VERSION 5.7 ;
  NOWIREEXTENSIONATPIN ON ;
  DIVIDERCHAR "/" ;
  BUSBITCHARS "[]" ;
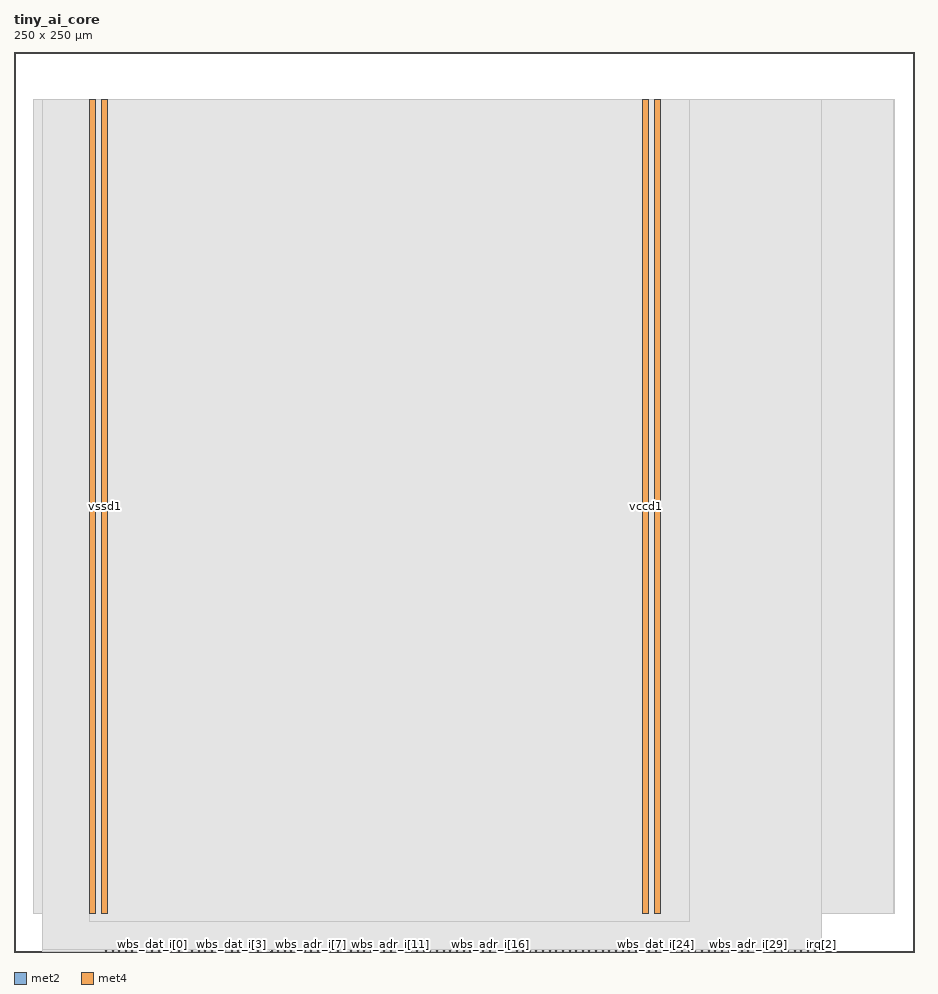
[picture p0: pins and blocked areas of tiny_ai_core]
MACRO tiny_ai_core
  CLASS BLOCK ;
  FOREIGN tiny_ai_core ;
  ORIGIN 0.000 0.000 ;
  SIZE 250.000 BY 250.000 ;
  PIN irq[0]
    DIRECTION OUTPUT ;
    USE SIGNAL ;
    ANTENNADIFFAREA 2.673000 ;
    PORT
      LAYER met2 ;
        RECT 220.430 0.000 220.710 0.280 ;
    END
  END irq[0]
  PIN irq[1]
    DIRECTION OUTPUT ;
    USE SIGNAL ;
    PORT
      LAYER met2 ;
        RECT 222.270 0.000 222.550 0.280 ;
    END
  END irq[1]
  PIN irq[2]
    DIRECTION OUTPUT ;
    USE SIGNAL ;
    PORT
      LAYER met2 ;
        RECT 224.110 0.000 224.390 0.280 ;
    END
  END irq[2]
  PIN vccd1
    DIRECTION INOUT ;
    USE POWER ;
    PORT
      LAYER met4 ;
        RECT 21.040 10.640 22.640 236.880 ;
    END
    PORT
      LAYER met4 ;
        RECT 174.640 10.640 176.240 236.880 ;
    END
  END vccd1
  PIN vssd1
    DIRECTION INOUT ;
    USE GROUND ;
    PORT
      LAYER met4 ;
        RECT 24.340 10.640 25.940 236.880 ;
    END
    PORT
      LAYER met4 ;
        RECT 177.940 10.640 179.540 236.880 ;
    END
  END vssd1
  PIN wb_clk_i
    DIRECTION INPUT ;
    USE SIGNAL ;
    ANTENNAGATEAREA 1.286700 ;
    ANTENNADIFFAREA 0.434700 ;
    PORT
      LAYER met2 ;
        RECT 25.390 0.000 25.670 0.280 ;
    END
  END wb_clk_i
  PIN wb_rst_i
    DIRECTION INPUT ;
    USE SIGNAL ;
    ANTENNAGATEAREA 0.647700 ;
    ANTENNADIFFAREA 0.434700 ;
    PORT
      LAYER met2 ;
        RECT 27.230 0.000 27.510 0.280 ;
    END
  END wb_rst_i
  PIN wbs_ack_o
    DIRECTION OUTPUT ;
    USE SIGNAL ;
    ANTENNADIFFAREA 2.673000 ;
    PORT
      LAYER met2 ;
        RECT 29.070 0.000 29.350 0.280 ;
    END
  END wbs_ack_o
  PIN wbs_adr_i[0]
    DIRECTION INPUT ;
    USE SIGNAL ;
    PORT
      LAYER met2 ;
        RECT 36.430 0.000 36.710 0.280 ;
    END
  END wbs_adr_i[0]
  PIN wbs_adr_i[10]
    DIRECTION INPUT ;
    USE SIGNAL ;
    ANTENNAGATEAREA 0.560700 ;
    ANTENNADIFFAREA 0.434700 ;
    PORT
      LAYER met2 ;
        RECT 98.990 0.000 99.270 0.280 ;
    END
  END wbs_adr_i[10]
  PIN wbs_adr_i[11]
    DIRECTION INPUT ;
    USE SIGNAL ;
    ANTENNAGATEAREA 0.647700 ;
    ANTENNADIFFAREA 0.434700 ;
    PORT
      LAYER met2 ;
        RECT 104.510 0.000 104.790 0.280 ;
    END
  END wbs_adr_i[11]
  PIN wbs_adr_i[12]
    DIRECTION INPUT ;
    USE SIGNAL ;
    ANTENNAGATEAREA 0.647700 ;
    ANTENNADIFFAREA 0.434700 ;
    PORT
      LAYER met2 ;
        RECT 110.030 0.000 110.310 0.280 ;
    END
  END wbs_adr_i[12]
  PIN wbs_adr_i[13]
    DIRECTION INPUT ;
    USE SIGNAL ;
    ANTENNAGATEAREA 0.647700 ;
    ANTENNADIFFAREA 0.434700 ;
    PORT
      LAYER met2 ;
        RECT 115.550 0.000 115.830 0.280 ;
    END
  END wbs_adr_i[13]
  PIN wbs_adr_i[14]
    DIRECTION INPUT ;
    USE SIGNAL ;
    ANTENNAGATEAREA 0.647700 ;
    ANTENNADIFFAREA 0.434700 ;
    PORT
      LAYER met2 ;
        RECT 121.070 0.000 121.350 0.280 ;
    END
  END wbs_adr_i[14]
  PIN wbs_adr_i[15]
    DIRECTION INPUT ;
    USE SIGNAL ;
    ANTENNAGATEAREA 0.647700 ;
    ANTENNADIFFAREA 0.434700 ;
    PORT
      LAYER met2 ;
        RECT 126.590 0.000 126.870 0.280 ;
    END
  END wbs_adr_i[15]
  PIN wbs_adr_i[16]
    DIRECTION INPUT ;
    USE SIGNAL ;
    ANTENNAGATEAREA 0.647700 ;
    ANTENNADIFFAREA 0.434700 ;
    PORT
      LAYER met2 ;
        RECT 132.110 0.000 132.390 0.280 ;
    END
  END wbs_adr_i[16]
  PIN wbs_adr_i[17]
    DIRECTION INPUT ;
    USE SIGNAL ;
    ANTENNAGATEAREA 0.647700 ;
    ANTENNADIFFAREA 0.434700 ;
    PORT
      LAYER met2 ;
        RECT 137.630 0.000 137.910 0.280 ;
    END
  END wbs_adr_i[17]
  PIN wbs_adr_i[18]
    DIRECTION INPUT ;
    USE SIGNAL ;
    ANTENNAGATEAREA 0.647700 ;
    ANTENNADIFFAREA 0.434700 ;
    PORT
      LAYER met2 ;
        RECT 143.150 0.000 143.430 0.280 ;
    END
  END wbs_adr_i[18]
  PIN wbs_adr_i[19]
    DIRECTION INPUT ;
    USE SIGNAL ;
    ANTENNAGATEAREA 0.647700 ;
    ANTENNADIFFAREA 0.434700 ;
    PORT
      LAYER met2 ;
        RECT 148.670 0.000 148.950 0.280 ;
    END
  END wbs_adr_i[19]
  PIN wbs_adr_i[1]
    DIRECTION INPUT ;
    USE SIGNAL ;
    PORT
      LAYER met2 ;
        RECT 43.790 0.000 44.070 0.280 ;
    END
  END wbs_adr_i[1]
  PIN wbs_adr_i[20]
    DIRECTION INPUT ;
    USE SIGNAL ;
    ANTENNAGATEAREA 0.647700 ;
    ANTENNADIFFAREA 0.434700 ;
    PORT
      LAYER met2 ;
        RECT 154.190 0.000 154.470 0.280 ;
    END
  END wbs_adr_i[20]
  PIN wbs_adr_i[21]
    DIRECTION INPUT ;
    USE SIGNAL ;
    ANTENNAGATEAREA 0.647700 ;
    ANTENNADIFFAREA 0.434700 ;
    PORT
      LAYER met2 ;
        RECT 159.710 0.000 159.990 0.280 ;
    END
  END wbs_adr_i[21]
  PIN wbs_adr_i[22]
    DIRECTION INPUT ;
    USE SIGNAL ;
    ANTENNAGATEAREA 0.647700 ;
    ANTENNADIFFAREA 0.434700 ;
    PORT
      LAYER met2 ;
        RECT 165.230 0.000 165.510 0.280 ;
    END
  END wbs_adr_i[22]
  PIN wbs_adr_i[23]
    DIRECTION INPUT ;
    USE SIGNAL ;
    ANTENNAGATEAREA 0.647700 ;
    ANTENNADIFFAREA 0.434700 ;
    PORT
      LAYER met2 ;
        RECT 170.750 0.000 171.030 0.280 ;
    END
  END wbs_adr_i[23]
  PIN wbs_adr_i[24]
    DIRECTION INPUT ;
    USE SIGNAL ;
    ANTENNAGATEAREA 0.647700 ;
    ANTENNADIFFAREA 0.434700 ;
    PORT
      LAYER met2 ;
        RECT 176.270 0.000 176.550 0.280 ;
    END
  END wbs_adr_i[24]
  PIN wbs_adr_i[25]
    DIRECTION INPUT ;
    USE SIGNAL ;
    ANTENNAGATEAREA 0.647700 ;
    ANTENNADIFFAREA 0.434700 ;
    PORT
      LAYER met2 ;
        RECT 181.790 0.000 182.070 0.280 ;
    END
  END wbs_adr_i[25]
  PIN wbs_adr_i[26]
    DIRECTION INPUT ;
    USE SIGNAL ;
    ANTENNAGATEAREA 0.560700 ;
    ANTENNADIFFAREA 0.434700 ;
    PORT
      LAYER met2 ;
        RECT 187.310 0.000 187.590 0.280 ;
    END
  END wbs_adr_i[26]
  PIN wbs_adr_i[27]
    DIRECTION INPUT ;
    USE SIGNAL ;
    ANTENNAGATEAREA 0.647700 ;
    ANTENNADIFFAREA 0.434700 ;
    PORT
      LAYER met2 ;
        RECT 192.830 0.000 193.110 0.280 ;
    END
  END wbs_adr_i[27]
  PIN wbs_adr_i[28]
    DIRECTION INPUT ;
    USE SIGNAL ;
    ANTENNAGATEAREA 0.647700 ;
    ANTENNADIFFAREA 0.434700 ;
    PORT
      LAYER met2 ;
        RECT 198.350 0.000 198.630 0.280 ;
    END
  END wbs_adr_i[28]
  PIN wbs_adr_i[29]
    DIRECTION INPUT ;
    USE SIGNAL ;
    ANTENNAGATEAREA 0.647700 ;
    ANTENNADIFFAREA 0.434700 ;
    PORT
      LAYER met2 ;
        RECT 203.870 0.000 204.150 0.280 ;
    END
  END wbs_adr_i[29]
  PIN wbs_adr_i[2]
    DIRECTION INPUT ;
    USE SIGNAL ;
    ANTENNAGATEAREA 0.647700 ;
    ANTENNADIFFAREA 0.434700 ;
    PORT
      LAYER met2 ;
        RECT 51.150 0.000 51.430 0.280 ;
    END
  END wbs_adr_i[2]
  PIN wbs_adr_i[30]
    DIRECTION INPUT ;
    USE SIGNAL ;
    ANTENNAGATEAREA 0.647700 ;
    ANTENNADIFFAREA 0.434700 ;
    PORT
      LAYER met2 ;
        RECT 209.390 0.000 209.670 0.280 ;
    END
  END wbs_adr_i[30]
  PIN wbs_adr_i[31]
    DIRECTION INPUT ;
    USE SIGNAL ;
    ANTENNAGATEAREA 0.647700 ;
    ANTENNADIFFAREA 0.434700 ;
    PORT
      LAYER met2 ;
        RECT 214.910 0.000 215.190 0.280 ;
    END
  END wbs_adr_i[31]
  PIN wbs_adr_i[3]
    DIRECTION INPUT ;
    USE SIGNAL ;
    ANTENNAGATEAREA 0.560700 ;
    ANTENNADIFFAREA 0.434700 ;
    PORT
      LAYER met2 ;
        RECT 58.510 0.000 58.790 0.280 ;
    END
  END wbs_adr_i[3]
  PIN wbs_adr_i[4]
    DIRECTION INPUT ;
    USE SIGNAL ;
    ANTENNAGATEAREA 0.647700 ;
    ANTENNADIFFAREA 0.434700 ;
    PORT
      LAYER met2 ;
        RECT 65.870 0.000 66.150 0.280 ;
    END
  END wbs_adr_i[4]
  PIN wbs_adr_i[5]
    DIRECTION INPUT ;
    USE SIGNAL ;
    ANTENNAGATEAREA 0.647700 ;
    ANTENNADIFFAREA 0.434700 ;
    PORT
      LAYER met2 ;
        RECT 71.390 0.000 71.670 0.280 ;
    END
  END wbs_adr_i[5]
  PIN wbs_adr_i[6]
    DIRECTION INPUT ;
    USE SIGNAL ;
    ANTENNAGATEAREA 0.560700 ;
    ANTENNADIFFAREA 0.434700 ;
    PORT
      LAYER met2 ;
        RECT 76.910 0.000 77.190 0.280 ;
    END
  END wbs_adr_i[6]
  PIN wbs_adr_i[7]
    DIRECTION INPUT ;
    USE SIGNAL ;
    ANTENNAGATEAREA 0.647700 ;
    ANTENNADIFFAREA 0.434700 ;
    PORT
      LAYER met2 ;
        RECT 82.430 0.000 82.710 0.280 ;
    END
  END wbs_adr_i[7]
  PIN wbs_adr_i[8]
    DIRECTION INPUT ;
    USE SIGNAL ;
    ANTENNAGATEAREA 0.647700 ;
    ANTENNADIFFAREA 0.434700 ;
    PORT
      LAYER met2 ;
        RECT 87.950 0.000 88.230 0.280 ;
    END
  END wbs_adr_i[8]
  PIN wbs_adr_i[9]
    DIRECTION INPUT ;
    USE SIGNAL ;
    ANTENNAGATEAREA 0.647700 ;
    ANTENNADIFFAREA 0.434700 ;
    PORT
      LAYER met2 ;
        RECT 93.470 0.000 93.750 0.280 ;
    END
  END wbs_adr_i[9]
  PIN wbs_cyc_i
    DIRECTION INPUT ;
    USE SIGNAL ;
    ANTENNAGATEAREA 0.560700 ;
    ANTENNADIFFAREA 0.434700 ;
    PORT
      LAYER met2 ;
        RECT 30.910 0.000 31.190 0.280 ;
    END
  END wbs_cyc_i
  PIN wbs_dat_i[0]
    DIRECTION INPUT ;
    USE SIGNAL ;
    ANTENNAGATEAREA 0.560700 ;
    ANTENNADIFFAREA 0.434700 ;
    PORT
      LAYER met2 ;
        RECT 38.270 0.000 38.550 0.280 ;
    END
  END wbs_dat_i[0]
  PIN wbs_dat_i[10]
    DIRECTION INPUT ;
    USE SIGNAL ;
    PORT
      LAYER met2 ;
        RECT 100.830 0.000 101.110 0.280 ;
    END
  END wbs_dat_i[10]
  PIN wbs_dat_i[11]
    DIRECTION INPUT ;
    USE SIGNAL ;
    PORT
      LAYER met2 ;
        RECT 106.350 0.000 106.630 0.280 ;
    END
  END wbs_dat_i[11]
  PIN wbs_dat_i[12]
    DIRECTION INPUT ;
    USE SIGNAL ;
    PORT
      LAYER met2 ;
        RECT 111.870 0.000 112.150 0.280 ;
    END
  END wbs_dat_i[12]
  PIN wbs_dat_i[13]
    DIRECTION INPUT ;
    USE SIGNAL ;
    PORT
      LAYER met2 ;
        RECT 117.390 0.000 117.670 0.280 ;
    END
  END wbs_dat_i[13]
  PIN wbs_dat_i[14]
    DIRECTION INPUT ;
    USE SIGNAL ;
    PORT
      LAYER met2 ;
        RECT 122.910 0.000 123.190 0.280 ;
    END
  END wbs_dat_i[14]
  PIN wbs_dat_i[15]
    DIRECTION INPUT ;
    USE SIGNAL ;
    PORT
      LAYER met2 ;
        RECT 128.430 0.000 128.710 0.280 ;
    END
  END wbs_dat_i[15]
  PIN wbs_dat_i[16]
    DIRECTION INPUT ;
    USE SIGNAL ;
    PORT
      LAYER met2 ;
        RECT 133.950 0.000 134.230 0.280 ;
    END
  END wbs_dat_i[16]
  PIN wbs_dat_i[17]
    DIRECTION INPUT ;
    USE SIGNAL ;
    PORT
      LAYER met2 ;
        RECT 139.470 0.000 139.750 0.280 ;
    END
  END wbs_dat_i[17]
  PIN wbs_dat_i[18]
    DIRECTION INPUT ;
    USE SIGNAL ;
    PORT
      LAYER met2 ;
        RECT 144.990 0.000 145.270 0.280 ;
    END
  END wbs_dat_i[18]
  PIN wbs_dat_i[19]
    DIRECTION INPUT ;
    USE SIGNAL ;
    PORT
      LAYER met2 ;
        RECT 150.510 0.000 150.790 0.280 ;
    END
  END wbs_dat_i[19]
  PIN wbs_dat_i[1]
    DIRECTION INPUT ;
    USE SIGNAL ;
    ANTENNAGATEAREA 0.560700 ;
    ANTENNADIFFAREA 0.434700 ;
    PORT
      LAYER met2 ;
        RECT 45.630 0.000 45.910 0.280 ;
    END
  END wbs_dat_i[1]
  PIN wbs_dat_i[20]
    DIRECTION INPUT ;
    USE SIGNAL ;
    PORT
      LAYER met2 ;
        RECT 156.030 0.000 156.310 0.280 ;
    END
  END wbs_dat_i[20]
  PIN wbs_dat_i[21]
    DIRECTION INPUT ;
    USE SIGNAL ;
    PORT
      LAYER met2 ;
        RECT 161.550 0.000 161.830 0.280 ;
    END
  END wbs_dat_i[21]
  PIN wbs_dat_i[22]
    DIRECTION INPUT ;
    USE SIGNAL ;
    PORT
      LAYER met2 ;
        RECT 167.070 0.000 167.350 0.280 ;
    END
  END wbs_dat_i[22]
  PIN wbs_dat_i[23]
    DIRECTION INPUT ;
    USE SIGNAL ;
    PORT
      LAYER met2 ;
        RECT 172.590 0.000 172.870 0.280 ;
    END
  END wbs_dat_i[23]
  PIN wbs_dat_i[24]
    DIRECTION INPUT ;
    USE SIGNAL ;
    PORT
      LAYER met2 ;
        RECT 178.110 0.000 178.390 0.280 ;
    END
  END wbs_dat_i[24]
  PIN wbs_dat_i[25]
    DIRECTION INPUT ;
    USE SIGNAL ;
    PORT
      LAYER met2 ;
        RECT 183.630 0.000 183.910 0.280 ;
    END
  END wbs_dat_i[25]
  PIN wbs_dat_i[26]
    DIRECTION INPUT ;
    USE SIGNAL ;
    PORT
      LAYER met2 ;
        RECT 189.150 0.000 189.430 0.280 ;
    END
  END wbs_dat_i[26]
  PIN wbs_dat_i[27]
    DIRECTION INPUT ;
    USE SIGNAL ;
    PORT
      LAYER met2 ;
        RECT 194.670 0.000 194.950 0.280 ;
    END
  END wbs_dat_i[27]
  PIN wbs_dat_i[28]
    DIRECTION INPUT ;
    USE SIGNAL ;
    PORT
      LAYER met2 ;
        RECT 200.190 0.000 200.470 0.280 ;
    END
  END wbs_dat_i[28]
  PIN wbs_dat_i[29]
    DIRECTION INPUT ;
    USE SIGNAL ;
    PORT
      LAYER met2 ;
        RECT 205.710 0.000 205.990 0.280 ;
    END
  END wbs_dat_i[29]
  PIN wbs_dat_i[2]
    DIRECTION INPUT ;
    USE SIGNAL ;
    ANTENNAGATEAREA 0.647700 ;
    ANTENNADIFFAREA 0.434700 ;
    PORT
      LAYER met2 ;
        RECT 52.990 0.000 53.270 0.280 ;
    END
  END wbs_dat_i[2]
  PIN wbs_dat_i[30]
    DIRECTION INPUT ;
    USE SIGNAL ;
    PORT
      LAYER met2 ;
        RECT 211.230 0.000 211.510 0.280 ;
    END
  END wbs_dat_i[30]
  PIN wbs_dat_i[31]
    DIRECTION INPUT ;
    USE SIGNAL ;
    PORT
      LAYER met2 ;
        RECT 216.750 0.000 217.030 0.280 ;
    END
  END wbs_dat_i[31]
  PIN wbs_dat_i[3]
    DIRECTION INPUT ;
    USE SIGNAL ;
    ANTENNAGATEAREA 0.647700 ;
    ANTENNADIFFAREA 0.434700 ;
    PORT
      LAYER met2 ;
        RECT 60.350 0.000 60.630 0.280 ;
    END
  END wbs_dat_i[3]
  PIN wbs_dat_i[4]
    DIRECTION INPUT ;
    USE SIGNAL ;
    ANTENNAGATEAREA 0.647700 ;
    ANTENNADIFFAREA 0.434700 ;
    PORT
      LAYER met2 ;
        RECT 67.710 0.000 67.990 0.280 ;
    END
  END wbs_dat_i[4]
  PIN wbs_dat_i[5]
    DIRECTION INPUT ;
    USE SIGNAL ;
    ANTENNAGATEAREA 0.647700 ;
    ANTENNADIFFAREA 0.434700 ;
    PORT
      LAYER met2 ;
        RECT 73.230 0.000 73.510 0.280 ;
    END
  END wbs_dat_i[5]
  PIN wbs_dat_i[6]
    DIRECTION INPUT ;
    USE SIGNAL ;
    ANTENNAGATEAREA 0.647700 ;
    ANTENNADIFFAREA 0.434700 ;
    PORT
      LAYER met2 ;
        RECT 78.750 0.000 79.030 0.280 ;
    END
  END wbs_dat_i[6]
  PIN wbs_dat_i[7]
    DIRECTION INPUT ;
    USE SIGNAL ;
    ANTENNAGATEAREA 0.647700 ;
    ANTENNADIFFAREA 0.434700 ;
    PORT
      LAYER met2 ;
        RECT 84.270 0.000 84.550 0.280 ;
    END
  END wbs_dat_i[7]
  PIN wbs_dat_i[8]
    DIRECTION INPUT ;
    USE SIGNAL ;
    ANTENNAGATEAREA 0.560700 ;
    ANTENNADIFFAREA 0.434700 ;
    PORT
      LAYER met2 ;
        RECT 89.790 0.000 90.070 0.280 ;
    END
  END wbs_dat_i[8]
  PIN wbs_dat_i[9]
    DIRECTION INPUT ;
    USE SIGNAL ;
    ANTENNAGATEAREA 0.560700 ;
    ANTENNADIFFAREA 0.434700 ;
    PORT
      LAYER met2 ;
        RECT 95.310 0.000 95.590 0.280 ;
    END
  END wbs_dat_i[9]
  PIN wbs_dat_o[0]
    DIRECTION OUTPUT ;
    USE SIGNAL ;
    ANTENNADIFFAREA 2.673000 ;
    PORT
      LAYER met2 ;
        RECT 40.110 0.000 40.390 0.280 ;
    END
  END wbs_dat_o[0]
  PIN wbs_dat_o[10]
    DIRECTION OUTPUT ;
    USE SIGNAL ;
    ANTENNADIFFAREA 2.673000 ;
    PORT
      LAYER met2 ;
        RECT 102.670 0.000 102.950 0.280 ;
    END
  END wbs_dat_o[10]
  PIN wbs_dat_o[11]
    DIRECTION OUTPUT ;
    USE SIGNAL ;
    ANTENNADIFFAREA 2.673000 ;
    PORT
      LAYER met2 ;
        RECT 108.190 0.000 108.470 0.280 ;
    END
  END wbs_dat_o[11]
  PIN wbs_dat_o[12]
    DIRECTION OUTPUT ;
    USE SIGNAL ;
    ANTENNADIFFAREA 2.673000 ;
    PORT
      LAYER met2 ;
        RECT 113.710 0.000 113.990 0.280 ;
    END
  END wbs_dat_o[12]
  PIN wbs_dat_o[13]
    DIRECTION OUTPUT ;
    USE SIGNAL ;
    ANTENNADIFFAREA 2.673000 ;
    PORT
      LAYER met2 ;
        RECT 119.230 0.000 119.510 0.280 ;
    END
  END wbs_dat_o[13]
  PIN wbs_dat_o[14]
    DIRECTION OUTPUT ;
    USE SIGNAL ;
    ANTENNADIFFAREA 2.673000 ;
    PORT
      LAYER met2 ;
        RECT 124.750 0.000 125.030 0.280 ;
    END
  END wbs_dat_o[14]
  PIN wbs_dat_o[15]
    DIRECTION OUTPUT ;
    USE SIGNAL ;
    ANTENNADIFFAREA 2.673000 ;
    PORT
      LAYER met2 ;
        RECT 130.270 0.000 130.550 0.280 ;
    END
  END wbs_dat_o[15]
  PIN wbs_dat_o[16]
    DIRECTION OUTPUT ;
    USE SIGNAL ;
    ANTENNADIFFAREA 2.673000 ;
    PORT
      LAYER met2 ;
        RECT 135.790 0.000 136.070 0.280 ;
    END
  END wbs_dat_o[16]
  PIN wbs_dat_o[17]
    DIRECTION OUTPUT ;
    USE SIGNAL ;
    ANTENNADIFFAREA 2.673000 ;
    PORT
      LAYER met2 ;
        RECT 141.310 0.000 141.590 0.280 ;
    END
  END wbs_dat_o[17]
  PIN wbs_dat_o[18]
    DIRECTION OUTPUT ;
    USE SIGNAL ;
    PORT
      LAYER met2 ;
        RECT 146.830 0.000 147.110 0.280 ;
    END
  END wbs_dat_o[18]
  PIN wbs_dat_o[19]
    DIRECTION OUTPUT ;
    USE SIGNAL ;
    PORT
      LAYER met2 ;
        RECT 152.350 0.000 152.630 0.280 ;
    END
  END wbs_dat_o[19]
  PIN wbs_dat_o[1]
    DIRECTION OUTPUT ;
    USE SIGNAL ;
    ANTENNADIFFAREA 2.673000 ;
    PORT
      LAYER met2 ;
        RECT 47.470 0.000 47.750 0.280 ;
    END
  END wbs_dat_o[1]
  PIN wbs_dat_o[20]
    DIRECTION OUTPUT ;
    USE SIGNAL ;
    PORT
      LAYER met2 ;
        RECT 157.870 0.000 158.150 0.280 ;
    END
  END wbs_dat_o[20]
  PIN wbs_dat_o[21]
    DIRECTION OUTPUT ;
    USE SIGNAL ;
    PORT
      LAYER met2 ;
        RECT 163.390 0.000 163.670 0.280 ;
    END
  END wbs_dat_o[21]
  PIN wbs_dat_o[22]
    DIRECTION OUTPUT ;
    USE SIGNAL ;
    ANTENNADIFFAREA 2.673000 ;
    PORT
      LAYER met2 ;
        RECT 168.910 0.000 169.190 0.280 ;
    END
  END wbs_dat_o[22]
  PIN wbs_dat_o[23]
    DIRECTION OUTPUT ;
    USE SIGNAL ;
    PORT
      LAYER met2 ;
        RECT 174.430 0.000 174.710 0.280 ;
    END
  END wbs_dat_o[23]
  PIN wbs_dat_o[24]
    DIRECTION OUTPUT ;
    USE SIGNAL ;
    PORT
      LAYER met2 ;
        RECT 179.950 0.000 180.230 0.280 ;
    END
  END wbs_dat_o[24]
  PIN wbs_dat_o[25]
    DIRECTION OUTPUT ;
    USE SIGNAL ;
    PORT
      LAYER met2 ;
        RECT 185.470 0.000 185.750 0.280 ;
    END
  END wbs_dat_o[25]
  PIN wbs_dat_o[26]
    DIRECTION OUTPUT ;
    USE SIGNAL ;
    ANTENNADIFFAREA 2.673000 ;
    PORT
      LAYER met2 ;
        RECT 190.990 0.000 191.270 0.280 ;
    END
  END wbs_dat_o[26]
  PIN wbs_dat_o[27]
    DIRECTION OUTPUT ;
    USE SIGNAL ;
    PORT
      LAYER met2 ;
        RECT 196.510 0.000 196.790 0.280 ;
    END
  END wbs_dat_o[27]
  PIN wbs_dat_o[28]
    DIRECTION OUTPUT ;
    USE SIGNAL ;
    ANTENNADIFFAREA 2.673000 ;
    PORT
      LAYER met2 ;
        RECT 202.030 0.000 202.310 0.280 ;
    END
  END wbs_dat_o[28]
  PIN wbs_dat_o[29]
    DIRECTION OUTPUT ;
    USE SIGNAL ;
    PORT
      LAYER met2 ;
        RECT 207.550 0.000 207.830 0.280 ;
    END
  END wbs_dat_o[29]
  PIN wbs_dat_o[2]
    DIRECTION OUTPUT ;
    USE SIGNAL ;
    ANTENNADIFFAREA 2.673000 ;
    PORT
      LAYER met2 ;
        RECT 54.830 0.000 55.110 0.280 ;
    END
  END wbs_dat_o[2]
  PIN wbs_dat_o[30]
    DIRECTION OUTPUT ;
    USE SIGNAL ;
    ANTENNADIFFAREA 2.673000 ;
    PORT
      LAYER met2 ;
        RECT 213.070 0.000 213.350 0.280 ;
    END
  END wbs_dat_o[30]
  PIN wbs_dat_o[31]
    DIRECTION OUTPUT ;
    USE SIGNAL ;
    PORT
      LAYER met2 ;
        RECT 218.590 0.000 218.870 0.280 ;
    END
  END wbs_dat_o[31]
  PIN wbs_dat_o[3]
    DIRECTION OUTPUT ;
    USE SIGNAL ;
    ANTENNADIFFAREA 2.673000 ;
    PORT
      LAYER met2 ;
        RECT 62.190 0.000 62.470 0.280 ;
    END
  END wbs_dat_o[3]
  PIN wbs_dat_o[4]
    DIRECTION OUTPUT ;
    USE SIGNAL ;
    ANTENNADIFFAREA 2.673000 ;
    PORT
      LAYER met2 ;
        RECT 69.550 0.000 69.830 0.280 ;
    END
  END wbs_dat_o[4]
  PIN wbs_dat_o[5]
    DIRECTION OUTPUT ;
    USE SIGNAL ;
    ANTENNADIFFAREA 2.673000 ;
    PORT
      LAYER met2 ;
        RECT 75.070 0.000 75.350 0.280 ;
    END
  END wbs_dat_o[5]
  PIN wbs_dat_o[6]
    DIRECTION OUTPUT ;
    USE SIGNAL ;
    ANTENNADIFFAREA 2.673000 ;
    PORT
      LAYER met2 ;
        RECT 80.590 0.000 80.870 0.280 ;
    END
  END wbs_dat_o[6]
  PIN wbs_dat_o[7]
    DIRECTION OUTPUT ;
    USE SIGNAL ;
    ANTENNADIFFAREA 2.673000 ;
    PORT
      LAYER met2 ;
        RECT 86.110 0.000 86.390 0.280 ;
    END
  END wbs_dat_o[7]
  PIN wbs_dat_o[8]
    DIRECTION OUTPUT ;
    USE SIGNAL ;
    ANTENNADIFFAREA 2.673000 ;
    PORT
      LAYER met2 ;
        RECT 91.630 0.000 91.910 0.280 ;
    END
  END wbs_dat_o[8]
  PIN wbs_dat_o[9]
    DIRECTION OUTPUT ;
    USE SIGNAL ;
    ANTENNADIFFAREA 2.673000 ;
    PORT
      LAYER met2 ;
        RECT 97.150 0.000 97.430 0.280 ;
    END
  END wbs_dat_o[9]
  PIN wbs_sel_i[0]
    DIRECTION INPUT ;
    USE SIGNAL ;
    ANTENNAGATEAREA 0.647700 ;
    ANTENNADIFFAREA 0.434700 ;
    PORT
      LAYER met2 ;
        RECT 41.950 0.000 42.230 0.280 ;
    END
  END wbs_sel_i[0]
  PIN wbs_sel_i[1]
    DIRECTION INPUT ;
    USE SIGNAL ;
    ANTENNAGATEAREA 0.647700 ;
    ANTENNADIFFAREA 0.434700 ;
    PORT
      LAYER met2 ;
        RECT 49.310 0.000 49.590 0.280 ;
    END
  END wbs_sel_i[1]
  PIN wbs_sel_i[2]
    DIRECTION INPUT ;
    USE SIGNAL ;
    ANTENNAGATEAREA 0.647700 ;
    ANTENNADIFFAREA 0.434700 ;
    PORT
      LAYER met2 ;
        RECT 56.670 0.000 56.950 0.280 ;
    END
  END wbs_sel_i[2]
  PIN wbs_sel_i[3]
    DIRECTION INPUT ;
    USE SIGNAL ;
    ANTENNAGATEAREA 0.647700 ;
    ANTENNADIFFAREA 0.434700 ;
    PORT
      LAYER met2 ;
        RECT 64.030 0.000 64.310 0.280 ;
    END
  END wbs_sel_i[3]
  PIN wbs_stb_i
    DIRECTION INPUT ;
    USE SIGNAL ;
    ANTENNAGATEAREA 0.647700 ;
    ANTENNADIFFAREA 0.434700 ;
    PORT
      LAYER met2 ;
        RECT 32.750 0.000 33.030 0.280 ;
    END
  END wbs_stb_i
  PIN wbs_we_i
    DIRECTION INPUT ;
    USE SIGNAL ;
    ANTENNAGATEAREA 0.647700 ;
    ANTENNADIFFAREA 0.434700 ;
    PORT
      LAYER met2 ;
        RECT 34.590 0.000 34.870 0.280 ;
    END
  END wbs_we_i
  OBS
      LAYER nwell ;
        RECT 5.330 10.795 244.450 236.830 ;
      LAYER li1 ;
        RECT 5.520 10.795 244.260 236.725 ;
      LAYER met1 ;
        RECT 5.520 10.640 244.260 236.880 ;
      LAYER met2 ;
        RECT 7.920 0.560 224.380 236.825 ;
        RECT 7.920 0.070 25.110 0.560 ;
        RECT 25.950 0.070 26.950 0.560 ;
        RECT 27.790 0.070 28.790 0.560 ;
        RECT 29.630 0.070 30.630 0.560 ;
        RECT 31.470 0.070 32.470 0.560 ;
        RECT 33.310 0.070 34.310 0.560 ;
        RECT 35.150 0.070 36.150 0.560 ;
        RECT 36.990 0.070 37.990 0.560 ;
        RECT 38.830 0.070 39.830 0.560 ;
        RECT 40.670 0.070 41.670 0.560 ;
        RECT 42.510 0.070 43.510 0.560 ;
        RECT 44.350 0.070 45.350 0.560 ;
        RECT 46.190 0.070 47.190 0.560 ;
        RECT 48.030 0.070 49.030 0.560 ;
        RECT 49.870 0.070 50.870 0.560 ;
        RECT 51.710 0.070 52.710 0.560 ;
        RECT 53.550 0.070 54.550 0.560 ;
        RECT 55.390 0.070 56.390 0.560 ;
        RECT 57.230 0.070 58.230 0.560 ;
        RECT 59.070 0.070 60.070 0.560 ;
        RECT 60.910 0.070 61.910 0.560 ;
        RECT 62.750 0.070 63.750 0.560 ;
        RECT 64.590 0.070 65.590 0.560 ;
        RECT 66.430 0.070 67.430 0.560 ;
        RECT 68.270 0.070 69.270 0.560 ;
        RECT 70.110 0.070 71.110 0.560 ;
        RECT 71.950 0.070 72.950 0.560 ;
        RECT 73.790 0.070 74.790 0.560 ;
        RECT 75.630 0.070 76.630 0.560 ;
        RECT 77.470 0.070 78.470 0.560 ;
        RECT 79.310 0.070 80.310 0.560 ;
        RECT 81.150 0.070 82.150 0.560 ;
        RECT 82.990 0.070 83.990 0.560 ;
        RECT 84.830 0.070 85.830 0.560 ;
        RECT 86.670 0.070 87.670 0.560 ;
        RECT 88.510 0.070 89.510 0.560 ;
        RECT 90.350 0.070 91.350 0.560 ;
        RECT 92.190 0.070 93.190 0.560 ;
        RECT 94.030 0.070 95.030 0.560 ;
        RECT 95.870 0.070 96.870 0.560 ;
        RECT 97.710 0.070 98.710 0.560 ;
        RECT 99.550 0.070 100.550 0.560 ;
        RECT 101.390 0.070 102.390 0.560 ;
        RECT 103.230 0.070 104.230 0.560 ;
        RECT 105.070 0.070 106.070 0.560 ;
        RECT 106.910 0.070 107.910 0.560 ;
        RECT 108.750 0.070 109.750 0.560 ;
        RECT 110.590 0.070 111.590 0.560 ;
        RECT 112.430 0.070 113.430 0.560 ;
        RECT 114.270 0.070 115.270 0.560 ;
        RECT 116.110 0.070 117.110 0.560 ;
        RECT 117.950 0.070 118.950 0.560 ;
        RECT 119.790 0.070 120.790 0.560 ;
        RECT 121.630 0.070 122.630 0.560 ;
        RECT 123.470 0.070 124.470 0.560 ;
        RECT 125.310 0.070 126.310 0.560 ;
        RECT 127.150 0.070 128.150 0.560 ;
        RECT 128.990 0.070 129.990 0.560 ;
        RECT 130.830 0.070 131.830 0.560 ;
        RECT 132.670 0.070 133.670 0.560 ;
        RECT 134.510 0.070 135.510 0.560 ;
        RECT 136.350 0.070 137.350 0.560 ;
        RECT 138.190 0.070 139.190 0.560 ;
        RECT 140.030 0.070 141.030 0.560 ;
        RECT 141.870 0.070 142.870 0.560 ;
        RECT 143.710 0.070 144.710 0.560 ;
        RECT 145.550 0.070 146.550 0.560 ;
        RECT 147.390 0.070 148.390 0.560 ;
        RECT 149.230 0.070 150.230 0.560 ;
        RECT 151.070 0.070 152.070 0.560 ;
        RECT 152.910 0.070 153.910 0.560 ;
        RECT 154.750 0.070 155.750 0.560 ;
        RECT 156.590 0.070 157.590 0.560 ;
        RECT 158.430 0.070 159.430 0.560 ;
        RECT 160.270 0.070 161.270 0.560 ;
        RECT 162.110 0.070 163.110 0.560 ;
        RECT 163.950 0.070 164.950 0.560 ;
        RECT 165.790 0.070 166.790 0.560 ;
        RECT 167.630 0.070 168.630 0.560 ;
        RECT 169.470 0.070 170.470 0.560 ;
        RECT 171.310 0.070 172.310 0.560 ;
        RECT 173.150 0.070 174.150 0.560 ;
        RECT 174.990 0.070 175.990 0.560 ;
        RECT 176.830 0.070 177.830 0.560 ;
        RECT 178.670 0.070 179.670 0.560 ;
        RECT 180.510 0.070 181.510 0.560 ;
        RECT 182.350 0.070 183.350 0.560 ;
        RECT 184.190 0.070 185.190 0.560 ;
        RECT 186.030 0.070 187.030 0.560 ;
        RECT 187.870 0.070 188.870 0.560 ;
        RECT 189.710 0.070 190.710 0.560 ;
        RECT 191.550 0.070 192.550 0.560 ;
        RECT 193.390 0.070 194.390 0.560 ;
        RECT 195.230 0.070 196.230 0.560 ;
        RECT 197.070 0.070 198.070 0.560 ;
        RECT 198.910 0.070 199.910 0.560 ;
        RECT 200.750 0.070 201.750 0.560 ;
        RECT 202.590 0.070 203.590 0.560 ;
        RECT 204.430 0.070 205.430 0.560 ;
        RECT 206.270 0.070 207.270 0.560 ;
        RECT 208.110 0.070 209.110 0.560 ;
        RECT 209.950 0.070 210.950 0.560 ;
        RECT 211.790 0.070 212.790 0.560 ;
        RECT 213.630 0.070 214.630 0.560 ;
        RECT 215.470 0.070 216.470 0.560 ;
        RECT 217.310 0.070 218.310 0.560 ;
        RECT 219.150 0.070 220.150 0.560 ;
        RECT 220.990 0.070 221.990 0.560 ;
        RECT 222.830 0.070 223.830 0.560 ;
      LAYER met3 ;
        RECT 21.050 8.335 187.615 236.805 ;
  END
END tiny_ai_core
END LIBRARY

